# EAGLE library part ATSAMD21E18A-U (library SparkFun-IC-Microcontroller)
SAM D21E 32-Pin QFN The SAMD21E is built around the 32-bit ARM Cortex-M0+ processor with up to 256KB of Flash and 32KB of SRAM. It operates at a maximum frequency of 48MHz.

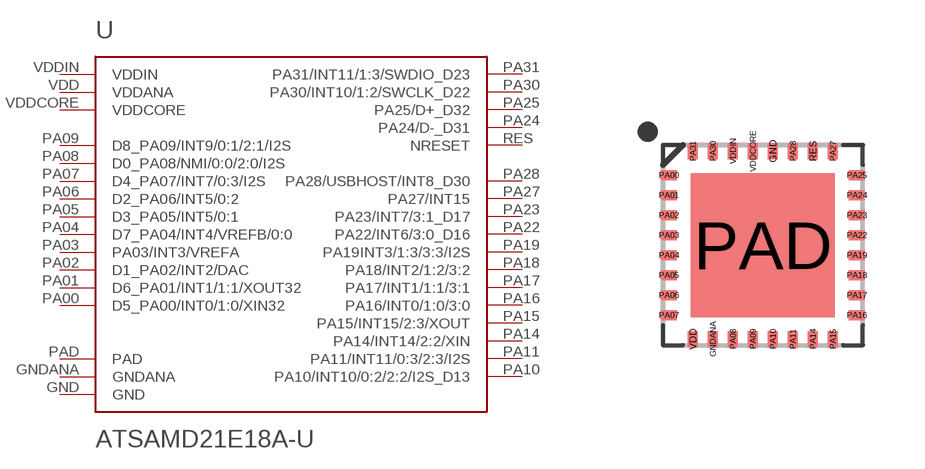
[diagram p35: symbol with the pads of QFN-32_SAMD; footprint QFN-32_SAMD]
Designator prefix U

## ATSAMD21E18A-U (PROD_ID: IC-14428)  [QFN-32_SAMD]
GND  GND  pwr
GNDANA  GNDANA  pwr
PA00  D5_PA00/INT0/1:0/XIN32
PA01  D6_PA01/INT1/1:1/XOUT32
PA02  D1_PA02/INT2/DAC
PA03  PA03/INT3/VREFA
PA04  D7_PA04/INT4/VREFB/0:0
PA05  D3_PA05/INT5/0:1
PA06  D2_PA06/INT5/0:2
PA07  D4_PA07/INT7/0:3/I2S
PA08  D0_PA08/NMI/0:0/2:0/I2S
PA09  D8_PA09/INT9/0:1/2:1/I2S
PA10  PA10/INT10/0:2/2:2/I2S_D13
PA11  PA11/INT11/0:3/2:3/I2S
PA14  PA14/INT14/2:2/XIN
PA15  PA15/INT15/2:3/XOUT
PA16  PA16/INT0/1:0/3:0
PA17  PA17/INT1/1:1/3:1
PA18  PA18/INT2/1:2/3:2
PA19  PA19INT3/1:3/3:3/I2S
PA22  PA22/INT6/3:0_D16
PA23  PA23/INT7/3:1_D17
PA24  PA24/D-_D31
PA25  PA25/D+_D32
PA27  PA27/INT15
PA28  PA28/USBHOST/INT8_D30
PA30  PA30/INT10/1:2/SWCLK_D22
PA31  PA31/INT11/1:3/SWDIO_D23
PAD  PAD  pwr
RES  NRESET
VDD  VDDANA  pwr
VDDCORE  VDDCORE  pwr
VDDIN  VDDIN  pwr

## Footprint QFN-32_SAMD (pad centres in mm)
SAMD21E QFN32 Physical Characteristics 5mm x 5mm Outline 32 Pins Pad Size: .25mm x.40mm Pitch: 0.5mm Ground Pad: 3.6mm x 3.6mm
smd 0.25 x 0.4: GND 0.21,2.31; GNDANA -1.29,-2.39; PA08 -0.79,-2.39; PA09 -0.29,-2.39; PA10 0.21,-2.39; PA11 0.71,-2.39; PA14 1.21,-2.39; PA15 1.71,-2.39; PA27 1.71,2.31; PA28 0.71,2.31; PA30 -1.29,2.31; PA31 -1.79,2.31; RES 1.21,2.31; VDD -1.79,-2.39; VDDCORE -0.29,2.31; VDDIN -0.79,2.31
smd 0.4 x 0.25: PA00 -2.39,1.71; PA01 -2.39,1.21; PA02 -2.39,0.71; PA03 -2.39,0.21; PA04 -2.39,-0.29; PA05 -2.39,-0.79; PA06 -2.39,-1.29; PA07 -2.39,-1.79; PA16 2.31,-1.79; PA17 2.31,-1.29; PA18 2.31,-0.79; PA19 2.31,-0.29; PA22 2.31,0.21; PA23 2.31,0.71; PA24 2.31,1.21; PA25 2.31,1.71
smd 3.6 x 3.6: PAD -0.04,-0.04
